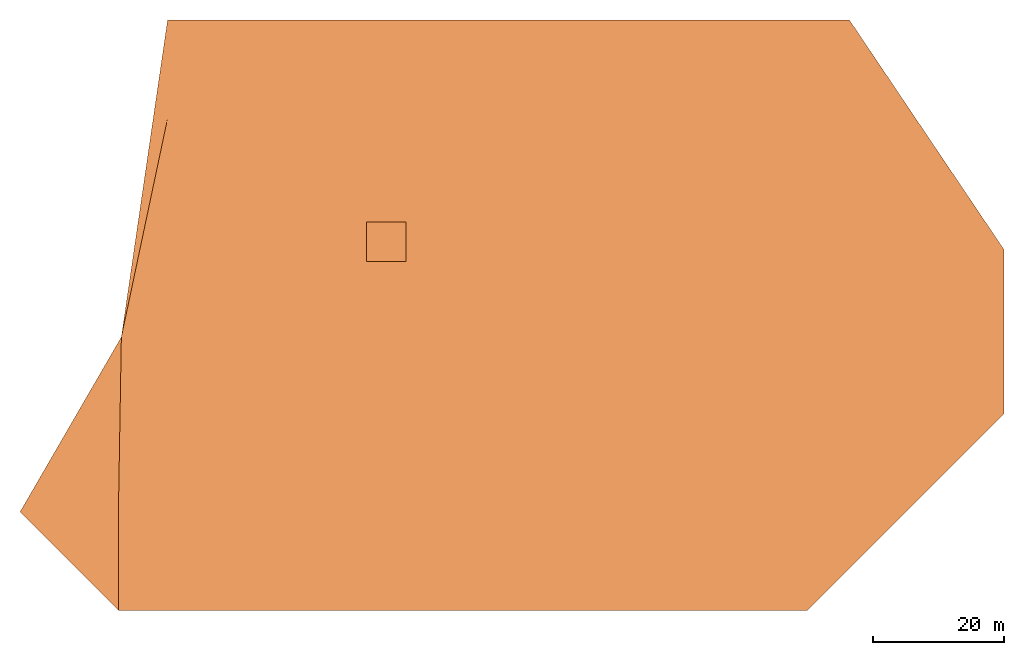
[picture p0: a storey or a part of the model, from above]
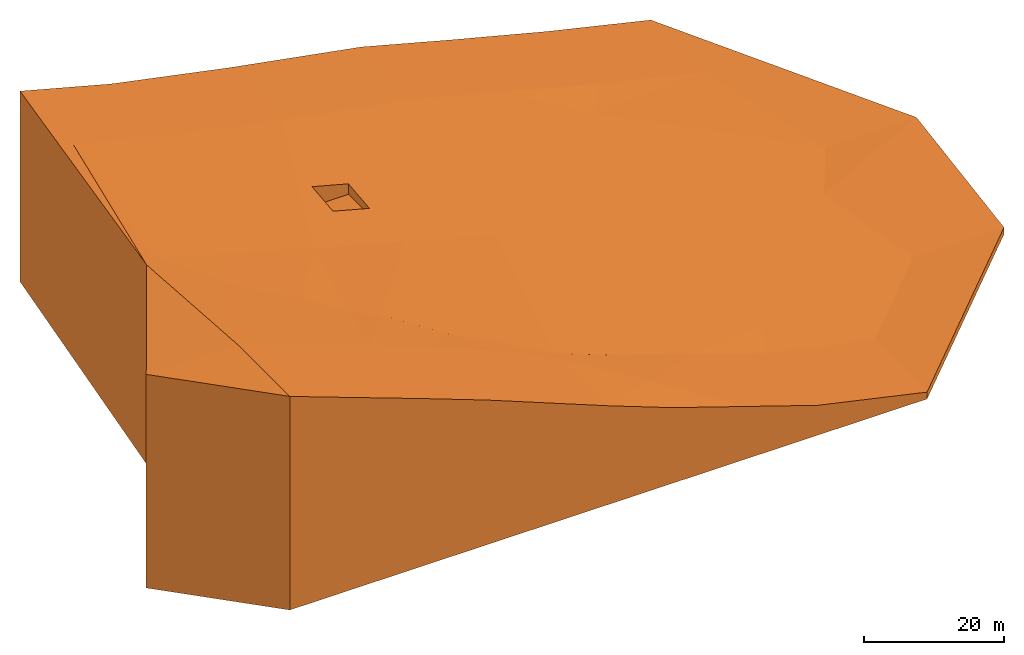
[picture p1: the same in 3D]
Properties of the parts of a building model (IFC2X3)

# File
Description: ViewDefinition [CoordinationView_V2.0], RevitIdentifiers [VersionGUID: 4cef613b-9c09-49b2-9ec8-052a137d9481, NumberOfSaves: 159], CoordinateReference [CoordinateBase: Shared Coordinates]
File name: STR, Analysis - 5 June.ifc
Time: 2025-06-09T13:41:58+01:00
Written by: ODA SDAI 24.11
Made in: Autodesk Revit 25.0.2.419 (ENU) - IFC 25.0.2.419

# IfcProject, 0001
LongName: Nome; Phase: Stato

# IfcSite, Default
RefLatitude: 45, 41, 48, 535766; RefLongitude: 7, 56, 43, 969573; RefElevation: 0 m

# IfcBuilding
Pset_BuildingCommon - NumberOfStoreys: 6

# IfcBuildingStorey: Level:Livello (7)
Pset_AirSideSystemInformation - sets with these values: 2
Name | LongName = Name | Elevation (m)
Soil | Soil | -25.8
Foundations | Foundations | -2
0 - Ground Floor | 0 - Ground Floor | 0
Ceiling | Ceiling | 2.7
1 - First Floor | 1 - First Floor | 3.1
Roof | Roof | 5.8
Top | Top | 8.26231

# IfcSpace: Baño 11:622634, 11
In: 0 - Ground Floor
LongName: Baño; InteriorOrExteriorSpace: INTERNAL
Pset_AirSideSystemInformation - Name: Baño; sets with these values: 2
Pset_SpaceCommon - Reference: Baño 11

# IfcSpace: Espacio 2:613980, 2
In: 0 - Ground Floor
LongName: Espacio; InteriorOrExteriorSpace: INTERNAL; Group: 1:622517
Pset_AirSideSystemInformation - Name: Espacio; sets with these values: 2
Pset_SpaceCommon - Reference: Espacio 2

# IfcSpace: Espacio 3:614526, 3
In: 1 - First Floor
LongName: Espacio; InteriorOrExteriorSpace: INTERNAL; Group: 2:622518
Pset_AirSideSystemInformation - Name: Espacio; sets with these values: 2
Pset_SpaceCommon - Reference: Espacio 3

# IfcSpace: Espacio 4:614530, 4
In: Roof
LongName: Espacio; InteriorOrExteriorSpace: INTERNAL; Group: 3:622765
Pset_AirSideSystemInformation - Name: Espacio; sets with these values: 2
Pset_SpaceCommon - Reference: Espacio 4

# IfcSpace: Habitación 10:622625, 10
In: 1 - First Floor
LongName: Habitación; InteriorOrExteriorSpace: INTERNAL
Pset_AirSideSystemInformation - Name: Habitación; sets with these values: 2
Pset_SpaceCommon - Reference: Habitación 10

# IfcSpace: Habitación 12:622643, 12
In: 0 - Ground Floor
LongName: Habitación; InteriorOrExteriorSpace: INTERNAL
Pset_AirSideSystemInformation - Name: Habitación; sets with these values: 2
Pset_SpaceCommon - Reference: Habitación 12

# IfcBeam: M_Glulam-Western Species:79X305 (7)
Type - PredefinedType: BEAM
Type - Pset_BeamCommon - IsExternal: no; LoadBearing: yes
Material: Softwood, Lumber
Pset_BeamCommon - Slope: 0 deg; Reference: 79X305
Pset_QuantityTakeOff - Reference: 79X305; sets with these values: 2
Name (M_Glulam-Western Species:79X305:...) | In | Span (m)
884572 | 1 - First Floor | 6
885537 | 1 - First Floor | 5.74
885714 | 1 - First Floor | 5.89
885947 | 1 - First Floor | 5.89
885982 | 1 - First Floor | 4.44
888757 | Roof | 5.8
893490 | 1 - First Floor | 1.7

# IfcBeam: M_Glulam-Western Species:79X305 (2)
In: Roof
Type - Pset_BeamCommon - IsExternal: no; LoadBearing: yes
Material: Softwood, Lumber
Pset_BeamCommon - Slope: 0 deg; Reference: 79X305; Span: 5.8128 m
Pset_QuantityTakeOff - Reference: 79X305; sets with these values: 2
Name (M_Glulam-Western Species:79X305:...)
888664
888702

# IfcBeam: M_Truss_Wood Web:35x90, M_Truss_Wood Web:35x90:877474
In: Roof
Type - PredefinedType: BEAM
Type - Pset_BeamCommon - IsExternal: no; LoadBearing: yes
Material: Softwood, Lumber
Pset_BeamCommon - Slope: 0 deg; Reference: 35x90; Span: 0.1397 m
Pset_QuantityTakeOff - Reference: 35x90; sets with these values: 2

# IfcBuildingElementProxy: 3D_Dian:Man, 3D_Dian:Man:568484
In: 0 - Ground Floor
Type - Material: Fabric - Red Brown, Fabric - Dark Skin, Fabric - White, Fabric - Suit Green, Fabric - Black, Fabric - Yellow
Pset_BuildingElementProxyCommon - Reference: Man; sets with these values: 2

# IfcBuildingElementProxy: 3D_Potted plant_2:3D_Potted plant_2, 3D_Potted plant_2:3D_Potted plant_2:575786
In: 0 - Ground Floor
Type - Material: 3D plant-1
Material: 3D plant-1, 3D plant-2, <Unnamed>
Pset_BuildingElementProxyCommon - Reference: 3D_Potted plant_2; sets with these values: 2

# IfcBuildingElementProxy: Gyrofocus_Fireplace_11749:Gyrofocus_Fireplace_11749, Gyrofocus_Fireplace_11749:Gyrofocus_Fireplace_11749:609935
In: 10
Type - Material: GyroFocus fire, GyroFocus Main Body, GyroFocus Flue Interior, GyroFocus Flue Exterior
Pset_BuildingElementProxyCommon - Reference: Gyrofocus_Fireplace_11749; sets with these values: 2

# IfcBuildingElementProxy: Toilet - Wall Based (1):Back to Wall, Toilet - Wall Based (1):Back to Wall:589035
In: 0 - Ground Floor
Type - Material: Porcelain, Plastic - Black
Pset_BuildingElementProxyCommon - Reference: Back to Wall; sets with these values: 2

# IfcBuildingElementProxy: Toposolid:Prato - 1200 mm, Toposolid:Prato - 1200 mm:529853
In: Soil
Material: Erba, Sabbia, Terra
Pset_BuildingElementProxyCommon - Reference: Prato - 1200 mm; sets with these values: 2

# IfcColumn: M_Timber-Column:140x140 (22)
Type - PredefinedType: COLUMN; Material: Softwood, Lumber
Type - Pset_ColumnCommon - IsExternal: no; LoadBearing: yes
Pset_ColumnCommon - Reference: 140x140
Pset_QuantityTakeOff - Reference: 140x140; sets with these values: 2
Name (M_Timber-Column:140x140:...) | In
873049 | 0 - Ground Floor
873255 | 0 - Ground Floor
873452 | 0 - Ground Floor
873625 | 0 - Ground Floor
873746 | 0 - Ground Floor
874393 | 0 - Ground Floor
874450 | 0 - Ground Floor
874625 | 0 - Ground Floor
876170 | 0 - Ground Floor
876317 | 0 - Ground Floor
886497 | 1 - First Floor
886581 | 1 - First Floor
886727 | 1 - First Floor
886896 | 1 - First Floor
886953 | 1 - First Floor
887054 | 1 - First Floor
887107 | 1 - First Floor
887154 | 1 - First Floor
887243 | 1 - First Floor
887408 | 1 - First Floor
891928 | 0 - Ground Floor
892140 | 0 - Ground Floor

# IfcDoor: M_Single-Flush:0915 x 2134mm, M_Single-Flush:0915 x 2134mm:557664
In: 0 - Ground Floor
Type - OperationType: SINGLE_SWING_LEFT; ParameterTakesPrecedence: no; Sizeable: no; Material: Glass
Type - M_Single-Flush:0915 x 2134mm:557664:1 - PanelOperation: SWINGING
Type - Pset_DoorCommon - IsExternal: no; ThermalTransmittance: 4.1165 kg/K/s3
OverallHeight: 2.134 m; OverallWidth: 0.915 m
Pset_DoorCommon - Reference: 0915 x 2134mm
Pset_QuantityTakeOff - Reference: 0915 x 2134mm

# IfcDoor: M_Single-Flush:0915 x 2134mm, M_Single-Flush:0915 x 2134mm:557665
In: 0 - Ground Floor
Type - OperationType: SINGLE_SWING_RIGHT; ParameterTakesPrecedence: no; Sizeable: no; Material: Glass
Type - M_Single-Flush:0915 x 2134mm:557665:1 - PanelOperation: SWINGING
Type - Pset_DoorCommon - IsExternal: no; ThermalTransmittance: 4.1165 kg/K/s3
OverallHeight: 2.134 m; OverallWidth: 0.915 m
Pset_DoorCommon - Reference: 0915 x 2134mm
Pset_QuantityTakeOff - Reference: 0915 x 2134mm

# IfcDoor: M_Single-Flush:0915 x 2134mm, M_Single-Flush:0915 x 2134mm:561959
In: 0 - Ground Floor
Type - OperationType: SINGLE_SWING_RIGHT; ParameterTakesPrecedence: no; Sizeable: no; Material: Glass
Type - M_Single-Flush:0915 x 2134mm:561959:1 - PanelOperation: SWINGING
Type - Pset_DoorCommon - IsExternal: no; ThermalTransmittance: 4.1165 kg/K/s3
OverallHeight: 2.134 m; OverallWidth: 0.915 m
Pset_DoorCommon - Reference: 0915 x 2134mm
Pset_QuantityTakeOff - Reference: 0915 x 2134mm

# IfcElementAssembly: M_Truss_Common Truss Attic Room 1L+1R_1B:W35_TCH90_VW90_DW90_BCH90 (5)
In: Roof
PredefinedType: TRUSS
Pset_QuantityTakeOff - Reference: W35_TCH90_VW90_DW90_BCH90
Name (M_Truss_Common Truss Attic Room 1L+1R_1B:W35_TCH90_VW90_DW90_BCH90:...)
888367
888486
888533
888573
889401

# IfcFurnishingElement: 009_Ikea_-_Hemnes_-_6_Dr:Black/Brown Finish, 009_Ikea_-_Hemnes_-_6_Dr:Black/Brown Finish:580983
In: 10
Type - Material: Pine - Black/Brown, Stainless Steel
Type - Pset_FurnitureTypeCommon - Description: 6 Drawer Chest
Type - Pset_ManufacturerTypeInformation - ArticleNumber: 701.212.49; Manufacturer: Ikea
Pset_QuantityTakeOff - Reference: Black/Brown Finish

# IfcFurnishingElement: 026_COALESSE_CIRCA_-_60_Inward_Facing_Lovesea:026_COALESSE_CIRCA_-_60_Inward_Facing_Lovesea (2)
In: 12
Type - Material: Furniture_Circa_Leg Finish (Metal), Furniture_Circa_Upholstery (Back), Furniture_Circa_Upholstery (Seat)
Type - Pset_FurnitureTypeCommon - Description: 60° Inward Facing Loveseat
Type - Pset_ManufacturerTypeInformation - Manufacturer: Coalesse
Pset_QuantityTakeOff - Reference: 026_COALESSE_CIRCA_-_60_Inward_Facing_Lovesea
Name (026_COALESSE_CIRCA_-_60_Inward_Facing_Lovesea:026_COALESSE_CIRCA_-_60_Inward_Facing_Lovesea:...)
569666
578600

# IfcFurnishingElement: 063_Ikea_Poang_Chair_And:063_Ikea_Poang_Chair_And, 063_Ikea_Poang_Chair_And:063_Ikea_Poang_Chair_And:576774
In: 0 - Ground Floor
Type - Material: Wood, Cushion
Pset_QuantityTakeOff - Reference: 063_Ikea_Poang_Chair_And

# IfcFurnishingElement: Base - Corner Unit:931 x 931 x 900mm, Base - Corner Unit:931 x 931 x 900mm:564095
In: 12
Type - Material: <Unnamed>
Type - Pset_FurnitureTypeCommon - Description: Corner
Pset_QuantityTakeOff - Reference: 931 x 931 x 900mm

# IfcFurnishingElement: Base - Double Door:600 x 900 x 900mm (2)
In: 12
Type - Material: <Unnamed>
Pset_QuantityTakeOff - Reference: 600 x 900 x 900mm
Name (Base - Double Door:600 x 900 x 900mm:...)
562498
568250

# IfcFurnishingElement: Bed05:Bed05, Bed05:Bed05:580437
In: 10
Type - Material: <Unnamed>
Pset_QuantityTakeOff - Reference: Bed05

# IfcFurnishingElement: Upper Cabinet - 1 Door with Glass:400 x 720 x 290mm (3)
In: 12
Type - Material: <Unnamed>, Glass
Type - Pset_ManufacturerTypeInformation - Manufacturer: Revit
Classification: C1030400 Uniformat (Uniformat)
Pset_QuantityTakeOff - Reference: 400 x 720 x 290mm
Name (Upper Cabinet - 1 Door with Glass:400 x 720 x 290mm:...)
587329
587426
587474

# IfcFurnishingElement: Wine Rack:600 x 300 x 900mm, Wine Rack:600 x 300 x 900mm:554740
In: 12
Type - Material: <Unnamed>
Pset_QuantityTakeOff - Reference: 600 x 300 x 900mm

# IfcMember: M_Truss_Wood Chord:35x90 (10)
In: Roof
Type - PredefinedType: CHORD; Material: <Unnamed>
Type - Pset_MemberCommon - IsExternal: no; LoadBearing: yes
Pset_MemberCommon - Slope: 0 deg; Reference: 35x90; Span: 0.045 m
Pset_QuantityTakeOff - Reference: 35x90
Name (M_Truss_Wood Chord:35x90:...)
889038
889039
889094
889095
889130
889131
889166
889167
889482
889483

# IfcMember: M_Truss_Wood Chord:35x90 (10)
In: Roof
Type - PredefinedType: CHORD; Material: <Unnamed>, Timber - C20
Type - Pset_MemberCommon - IsExternal: no; LoadBearing: yes
Material: Timber - C20
Pset_MemberCommon - Slope: 0 deg; Reference: 35x90
Pset_QuantityTakeOff - Reference: 35x90
Name (M_Truss_Wood Chord:35x90:...) | Span (m)
888490 | 4.29626
888491 | 4.29626
888537 | 4.29558
888538 | 4.29558
888577 | 4.29614
888578 | 4.29614
889031 | 4.29553
889032 | 4.29553
889405 | 4.29614
889406 | 4.29614

# IfcMember: M_Truss_Wood Chord:35x90 (10)
In: Roof
Type - PredefinedType: CHORD; Material: Timber - C20
Type - Pset_MemberCommon - IsExternal: no; LoadBearing: yes
Pset_MemberCommon - Slope: 0 deg; Reference: 35x90
Pset_QuantityTakeOff - Reference: 35x90
Name (M_Truss_Wood Chord:35x90:...) | Span (m)
889033 | 5.889
889037 | 2.3331
889090 | 5.89
889092 | 2.3341
889126 | 5.88908
889128 | 2.33318
889162 | 5.8902
889164 | 2.3343
889478 | 5.89
889480 | 2.3341

# IfcMember: M_Truss_Wood Web:35x90 (30)
In: Roof
Type - PredefinedType: BRACE; Material: <Unnamed>
Type - Pset_MemberCommon - IsExternal: no; LoadBearing: yes
Pset_MemberCommon - Slope: 0 deg; Reference: 35x90; Span: 0.045 m
Pset_QuantityTakeOff - Reference: 35x90
Name (M_Truss_Wood Web:35x90:...)
888495
888542
888582
889030
889036
889042
889043
889044
889045
889088
889096
889097
889098
889099
889124
889132
889133
889134
889135
889160
889168
889169
889170
889171
889410
889476
889484
889485
889486
889487

# IfcMember: M_Truss_Wood Web:35x90 (40)
In: Roof
Type - PredefinedType: BRACE; Material: Timber - C20
Type - Pset_MemberCommon - IsExternal: no; LoadBearing: yes
Pset_MemberCommon - Slope: 0 deg; Reference: 35x90
Pset_QuantityTakeOff - Reference: 35x90
Name (M_Truss_Wood Web:35x90:...) | Span (m)
888493 | 0.145065
888494 | 0.145065
888496 | 1.19423
888497 | 1.19423
888540 | 0.145065
888541 | 0.145065
888543 | 1.19403
888544 | 1.19403
888580 | 0.145065
888581 | 0.145065
888583 | 1.19419
888584 | 1.19419
889034 | 0.145065
889035 | 0.145065
889040 | 1.19402
889041 | 1.19402
889046 | 1.00837
889047 | 1.00837
889048 | 0.712047
889049 | 0.712047
889089 | 1.00852
889091 | 1.00852
889093 | 0.712352
889100 | 0.712352
889125 | 1.00838
889127 | 1.00838
889129 | 0.712071
889136 | 0.712071
889161 | 1.00855
889163 | 1.00855
889165 | 0.712414
889172 | 0.712414
889408 | 0.145065
889409 | 0.145065
889411 | 1.19419
889412 | 1.19419
889477 | 1.00852
889479 | 1.00852
889481 | 0.712353
889488 | 0.712353

# IfcMember: Stringer:Stringer - 50mm Width (6)
In: 0 - Ground Floor
Type - PredefinedType: STRINGER
Material: Default - Calcestruzzo
Pset_MemberCommon - IsExternal: no; Reference: Stringer - 50mm Width
Pset_QuantityTakeOff - Reference: Stringer - 50mm Width
Name (Assembled Stair:Stair:...) | Slope (deg)
593008 Stringer 1 | 35.2176
593008 Stringer 2 | 35.2176
593008 Stringer 3 | 35.2176
593008 Stringer 4 | 35.2176
593008 Stringer 5 | 0
593008 Stringer 6 | 0

# IfcOpeningElement: Opening (6)
Name | In
Basic Wall:interior v1:609449 | 0 - Ground Floor | Pset_OpeningElementCommon - Reference: interior v1; sets with these values: 2
Bay - Rectangular(2):Bay - Rectangular(2):573645:1 | 0 - Ground Floor
M_Single-Flush:0915 x 2134mm:557664:1 | 0 - Ground Floor
M_Single-Flush:0915 x 2134mm:557665:1 | 0 - Ground Floor
M_Single-Flush:0915 x 2134mm:561959:1 | 0 - Ground Floor
Bay - Rectangular(2):Bay - Rectangular(2):582244:1 | 1 - First Floor

# IfcOpeningElement: Recess, Toposolid:Prato - 1200 mm:529853
In: Soil
Pset_OpeningElementCommon - Reference: Toposolid 1; sets with these values: 2

# IfcRailing: Railing:900mm Pipe (2)
In: 0 - Ground Floor
Type - Pset_RailingCommon - IsExternal: no
Material: <Unnamed>
Pset_QuantityTakeOff - Reference: 900mm Pipe
Pset_RailingCommon - Reference: 900mm Pipe; Height: 0.9 m
Name (Railing:900mm Pipe:...)
593021
593025

# IfcRailing: Railing:Glass Panel - Bottom Fill (4)
Type - Pset_RailingCommon - IsExternal: no
Material: Metal - Stainless Steel,Polished, Glass, <Unnamed>
Pset_QuantityTakeOff - Reference: Glass Panel - Bottom Fill
Pset_RailingCommon - Reference: Glass Panel - Bottom Fill; Height: 0.9 m
Name (Railing:Glass Panel - Bottom Fill:...) | In
571528 | 0 - Ground Floor
573616 | 0 - Ground Floor
582329 | 1 - First Floor
582410 | 1 - First Floor

# IfcRoof: Basic Roof:Latero Cementizio - 27 cm, Basic Roof:Latero Cementizio - 27 cm:180624
In: Roof
Material: Ghiaia 0.05 m, bituminous waterproof sheet 0.008 m, wood cement panel 0.022 m, wood fiber 0.18 m, vapor barrier 0.0035 m, osb panel 0.025 m
Pset_QuantityTakeOff - Reference: Latero Cementizio - 27 cm
Pset_RoofCommon - IsExternal: yes; Reference: Latero Cementizio - 27 cm; ProjectedArea: 49.256 m2; TotalArea: 60.1305 m2

# IfcSlab: Basic Roof:Latero Cementizio - 27 cm (2)
In: Roof
PredefinedType: ROOF; Material: Ghiaia 0.05 m, bituminous waterproof sheet 0.008 m, wood cement panel 0.022 m, wood fiber 0.18 m, vapor barrier 0.0035 m, osb panel 0.025 m
Pset_QuantityTakeOff - Reference: Latero Cementizio - 27 cm; sets with these values: 2
Pset_SlabCommon - IsExternal: yes; Reference: Latero Cementizio - 27 cm; PitchAngle: 35 deg

# IfcSlab: Floor:Calcestruzzo da 160 mm con soletta metallica da 50 mm, Floor:Calcestruzzo da 160 mm con soletta metallica da 50 mm:620854
In: 0 - Ground Floor
Type - PredefinedType: FLOOR; Material: Default - Calcestruzzo 0.21 m
Type - Pset_SlabCommon - IsExternal: no; ThermalTransmittance: 1000000000000000019884624838656 kg/K/s3
Pset_QuantityTakeOff - Reference: Calcestruzzo da 160 mm con soletta metallica da 50 mm; sets with these values: 2
Pset_SlabCommon - LoadBearing: no; PitchAngle: 0 deg; Reference: Calcestruzzo da 160 mm con soletta metallica da 50 mm

# IfcSlab: Floor:Latero Cementizio - 40 cm (2)
Type - PredefinedType: FLOOR; Material: Wood Vinyl Finish 0.015 m, wood fiber 0.02 m, Structure, Timber Joist/Rafter Layer 0.2 m, cross laminated timber 0.02 m, vapor barrier 0.003 m, Ghiaia 0.05 m
Type - Pset_SlabCommon - IsExternal: no; ThermalTransmittance: 0.416163 kg/K/s3
Pset_QuantityTakeOff - Reference: Latero Cementizio - 40 cm; sets with these values: 2
Pset_SlabCommon - Reference: Latero Cementizio - 40 cm; PitchAngle: 0 deg
Name (Floor:Latero Cementizio - 40 cm:...) | In | LoadBearing
151336 | 0 - Ground Floor | no
604668 | 1 - First Floor | yes

# IfcSlab: Foundation Slab:Platea, Foundation Slab:Platea:538365
In: Foundations
Type - PredefinedType: BASESLAB; Material: Lime Plaster 0.02 m, Cocrete Slab 0.25 m, Concrete Screed 0.06 m, XPS 0.1 m, Sand 0.04 m, air cavity 0.05 m, Natural Stone 0.05 m
Type - Pset_SlabCommon - IsExternal: no; ThermalTransmittance: 0.18502 kg/K/s3
Pset_QuantityTakeOff - Reference: Platea; sets with these values: 2
Pset_SlabCommon - PitchAngle: 0 deg; Reference: Platea; LoadBearing: yes

# IfcSlab: Non-Monolithic Landing:Non-Monolithic Landing, Assembled Stair:Stair:593008 Landing 1
In: 0 - Ground Floor
Type - PredefinedType: LANDING
Type - Pset_SlabCommon - IsExternal: no
Material: Default - Calcestruzzo
Pset_QuantityTakeOff - Reference: Non-Monolithic Landing; sets with these values: 2
Pset_SlabCommon - Reference: Non-Monolithic Landing

# IfcStair: Assembled Stair:Industrial and Assembly, Assembled Stair:Stair:593008
In: 0 - Ground Floor
ShapeType: QUARTER_TURN_STAIR
Pset_QuantityTakeOff - Reference: Industrial and Assembly
Pset_StairCommon - IsExternal: no; Reference: Industrial and Assembly; NumberOfRiser: 15; NumberOfTreads: 13; RiserHeight: 0.176471 m; TreadLength: 0.25 m

# IfcStairFlight: Non-Monolithic Run:50mm Tread 13mm Riser with Nosing (2)
In: 0 - Ground Floor
Type - PredefinedType: STRAIGHT
Type - Pset_StairFlightCommon - NosingLength: 0 m
RiserHeight: 0.578972 m; TreadLength: 0.82021 m; Material: Default - Calcestruzzo
Pset_QuantityTakeOff - Reference: 50mm Tread 13mm Riser with Nosing
Pset_StairFlightCommon - Reference: 50mm Tread 13mm Riser with Nosing; RiserHeight: 0.176471 m; TreadLength: 0.25 m; WalkingLineOffset: 1.64042 m; TreadLengthAtOffset: 0.25 m; TreadLengthAtInnerSide: 0.25 m
Name (Assembled Stair:Stair:...) | NumberOfRiser = Pset_StairFlightCommon, NumberOfRiser | NumberOfTreads = Pset_StairFlightCommon, NumberOfTreads
593008 Run 1 | 3 | 2
593008 Run 2 | 12 | 11

# IfcWall: Basic Wall:external wall 2, Basic Wall:external wall 2:152922
In: 1 - First Floor
Type - PredefinedType: STANDARD; Material: gypsum plaster 0.025 m, wood fiber 0.02 m, osb panel 0.02 m, wood fiber 0.02 m, water proof and wind proof sheet 0.005 m, osb panel 0.02 m, mineral rock wool 0.04 m, air cavity 0.05 m, plaster board panel 0.03 m
Type - Pset_WallCommon - IsExternal: yes; ThermalTransmittance: 0.338354 kg/K/s3
Pset_QuantityTakeOff - Reference: external wall 2; sets with these values: 2
Pset_WallCommon - Reference: external wall 2; LoadBearing: no; ExtendToStructure: yes

# IfcWallStandardCase: Basic Wall:Exterior - Brick on Mtl. Stud (2)
Type - PredefinedType: STANDARD; Material: Glass, Clear Glazing 0.004 m
Type - Pset_WallCommon - IsExternal: yes; ThermalTransmittance: 275 kg/K/s3
Pset_QuantityTakeOff - Reference: Exterior - Brick on Mtl. Stud; sets with these values: 2
Pset_WallCommon - LoadBearing: no; Reference: Exterior - Brick on Mtl. Stud
Name (Basic Wall:Exterior - Brick on Mtl. Stud:...) | In | ExtendToStructure
557663 | 0 - Ground Floor | no
578947 | 1 - First Floor | yes

# IfcWallStandardCase: Basic Wall:external wall 2 (5)
Type - PredefinedType: STANDARD; Material: gypsum plaster 0.025 m, wood fiber 0.02 m, osb panel 0.02 m, wood fiber 0.02 m, water proof and wind proof sheet 0.005 m, osb panel 0.02 m, mineral rock wool 0.04 m, air cavity 0.05 m, plaster board panel 0.03 m
Type - Pset_WallCommon - IsExternal: yes; ThermalTransmittance: 0.338354 kg/K/s3
Pset_QuantityTakeOff - Reference: external wall 2; sets with these values: 2
Pset_WallCommon - Reference: external wall 2; LoadBearing: no
Name (Basic Wall:external wall 2:...) | In | ExtendToStructure
140683 | 0 - Ground Floor | no
140686 | 0 - Ground Floor | no
152919 | 1 - First Floor | yes
152920 | 1 - First Floor | yes
350663 | 0 - Ground Floor | no

# IfcWallStandardCase: Basic Wall:interior v1 (6)
In: 0 - Ground Floor
Type - PredefinedType: STANDARD; Material: Tiles 0.004 m, Cement Board 0.046 m, water proof and wind proof sheet 0.004 m, cross laminated timber 0.02 m, polyethylene plastic sheeting 0.006 m, cross laminated timber 0.02 m, acoustic oak wood wall cladding 0.02 m, Gypsum Wall Board 0.012 m
Type - Pset_WallCommon - IsExternal: no; ThermalTransmittance: 1.74548 kg/K/s3
Pset_QuantityTakeOff - Reference: interior v1; sets with these values: 2
Pset_WallCommon - LoadBearing: no; Reference: interior v1
Name (Basic Wall:interior v1:...) | ExtendToStructure
557600 | no
561443 | no
561958 | yes
615631 | no
620220 | no
620365 | no

# IfcWindow: Bay - Rectangular(2):Bay - Rectangular(2) (2)
Type - OperationType: USERDEFINED; ParameterTakesPrecedence: no; Sizeable: no; Material: Window Frame, Glass, Rooing - Slate Blue, Roofing - Ship Lap Boarding
Type - Pset_ManufacturerTypeInformation - Manufacturer: Revit
Type - Pset_WindowCommon - IsExternal: no
OverallHeight: 1.2 m; OverallWidth: 1.2 m
Pset_QuantityTakeOff - Reference: Bay - Rectangular(2)
Pset_WindowCommon - Reference: Bay - Rectangular(2)
Name (Bay - Rectangular(2):Bay - Rectangular(2):...) | In
573645 | 0 - Ground Floor | Pset_WindowCommon - IsExternal: yes
582244 | 1 - First Floor

# IfcZone (3)
Name | Reference
1:622517 | 1
2:622518 | 2
3:622765 | 3
